One B-rep face of a CAD part: STEP entity #11586.
In plain terms, the planar face has unit normal (0, 1, 0).
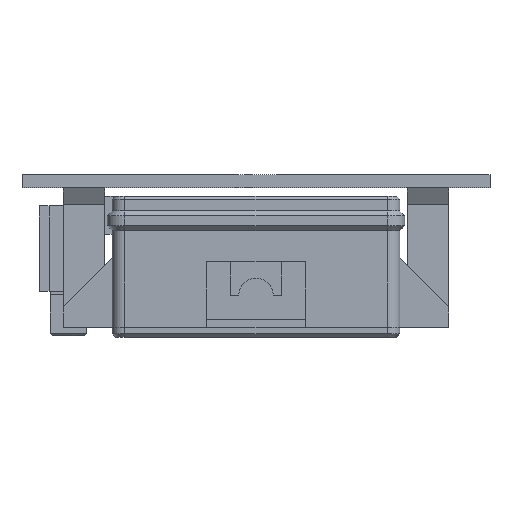
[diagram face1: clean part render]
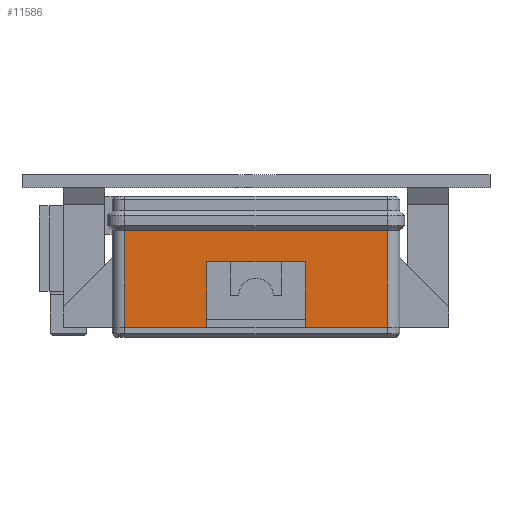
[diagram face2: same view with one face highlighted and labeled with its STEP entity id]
Its self-contained STEP definition (entity closure, numbers rounded to 3 decimals):
#2296 = PLANE('',#2297);
#2297 = AXIS2_PLACEMENT_3D('',#2298,#2299,#2300);
#2298 = CARTESIAN_POINT('',(-35.05,-46.3,32.));
#2299 = DIRECTION('',(0.,0.,1.));
#2300 = DIRECTION('',(1.,0.,-0.));
#5580 = VERTEX_POINT('',#5581);
#5581 = CARTESIAN_POINT('',(32.05,46.3,32.));
#5596 = CYLINDRICAL_SURFACE('',#5597,3.);
#5597 = AXIS2_PLACEMENT_3D('',#5598,#5599,#5600);
#5598 = CARTESIAN_POINT('',(32.05,43.3,0.));
#5599 = DIRECTION('',(0.,0.,1.));
#5600 = DIRECTION('',(1.,0.,-0.));
#5608 = EDGE_CURVE('',#5609,#5580,#5611,.T.);
#5609 = VERTEX_POINT('',#5610);
#5610 = CARTESIAN_POINT('',(12.,46.3,32.));
#5611 = SURFACE_CURVE('',#5612,(#5616,#5623),.PCURVE_S1.);
#5612 = LINE('',#5613,#5614);
#5613 = CARTESIAN_POINT('',(-35.05,46.3,32.));
#5614 = VECTOR('',#5615,1.);
#5615 = DIRECTION('',(1.,0.,-0.));
#5616 = PCURVE('',#2296,#5617);
#5617 = DEFINITIONAL_REPRESENTATION('',(#5618),#5622);
#5618 = LINE('',#5619,#5620);
#5619 = CARTESIAN_POINT('',(0.,92.6));
#5620 = VECTOR('',#5621,1.);
#5621 = DIRECTION('',(1.,0.));
#5622 = ( GEOMETRIC_REPRESENTATION_CONTEXT(2) 
PARAMETRIC_REPRESENTATION_CONTEXT() REPRESENTATION_CONTEXT('2D SPACE',''
  ) );
#5623 = PCURVE('',#5624,#5629);
#5624 = PLANE('',#5625);
#5625 = AXIS2_PLACEMENT_3D('',#5626,#5627,#5628);
#5626 = CARTESIAN_POINT('',(-35.05,46.3,0.));
#5627 = DIRECTION('',(-0.,1.,0.));
#5628 = DIRECTION('',(0.,0.,1.));
#5629 = DEFINITIONAL_REPRESENTATION('',(#5630),#5634);
#5630 = LINE('',#5631,#5632);
#5631 = CARTESIAN_POINT('',(32.,0.));
#5632 = VECTOR('',#5633,1.);
#5633 = DIRECTION('',(0.,1.));
#5634 = ( GEOMETRIC_REPRESENTATION_CONTEXT(2) 
PARAMETRIC_REPRESENTATION_CONTEXT() REPRESENTATION_CONTEXT('2D SPACE',''
  ) );
#5652 = PLANE('',#5653);
#5653 = AXIS2_PLACEMENT_3D('',#5654,#5655,#5656);
#5654 = CARTESIAN_POINT('',(12.,43.5,16.));
#5655 = DIRECTION('',(1.,0.,-0.));
#5656 = DIRECTION('',(0.,0.,1.));
#7690 = CYLINDRICAL_SURFACE('',#7691,3.);
#7691 = AXIS2_PLACEMENT_3D('',#7692,#7693,#7694);
#7692 = CARTESIAN_POINT('',(-32.05,43.3,0.));
#7693 = DIRECTION('',(0.,0.,1.));
#7694 = DIRECTION('',(-1.,-0.,0.));
#7718 = PLANE('',#7719);
#7719 = AXIS2_PLACEMENT_3D('',#7720,#7721,#7722);
#7720 = CARTESIAN_POINT('',(-35.05,-46.3,32.));
#7721 = DIRECTION('',(0.,0.,1.));
#7722 = DIRECTION('',(1.,0.,-0.));
#11537 = VERTEX_POINT('',#11538);
#11538 = CARTESIAN_POINT('',(32.05,46.3,8.4));
#11565 = EDGE_CURVE('',#11537,#5580,#11566,.T.);
#11566 = SURFACE_CURVE('',#11567,(#11571,#11578),.PCURVE_S1.);
#11567 = LINE('',#11568,#11569);
#11568 = CARTESIAN_POINT('',(32.05,46.3,0.));
#11569 = VECTOR('',#11570,1.);
#11570 = DIRECTION('',(0.,0.,1.));
#11571 = PCURVE('',#5596,#11572);
#11572 = DEFINITIONAL_REPRESENTATION('',(#11573),#11577);
#11573 = LINE('',#11574,#11575);
#11574 = CARTESIAN_POINT('',(1.571,0.));
#11575 = VECTOR('',#11576,1.);
#11576 = DIRECTION('',(0.,1.));
#11577 = ( GEOMETRIC_REPRESENTATION_CONTEXT(2) 
PARAMETRIC_REPRESENTATION_CONTEXT() REPRESENTATION_CONTEXT('2D SPACE',''
  ) );
#11578 = PCURVE('',#5624,#11579);
#11579 = DEFINITIONAL_REPRESENTATION('',(#11580),#11584);
#11580 = LINE('',#11581,#11582);
#11581 = CARTESIAN_POINT('',(0.,67.1));
#11582 = VECTOR('',#11583,1.);
#11583 = DIRECTION('',(1.,0.));
#11584 = ( GEOMETRIC_REPRESENTATION_CONTEXT(2) 
PARAMETRIC_REPRESENTATION_CONTEXT() REPRESENTATION_CONTEXT('2D SPACE',''
  ) );
#11586 = ADVANCED_FACE('',(#11587),#5624,.T.);
#11587 = FACE_BOUND('',#11588,.T.);
#11588 = EDGE_LOOP('',(#11589,#11617,#11640,#11663,#11689,#11715,#11734,
    #11735));
#11589 = ORIENTED_EDGE('',*,*,#11590,.F.);
#11590 = EDGE_CURVE('',#11591,#11537,#11593,.T.);
#11591 = VERTEX_POINT('',#11592);
#11592 = CARTESIAN_POINT('',(-32.05,46.3,8.4));
#11593 = SURFACE_CURVE('',#11594,(#11598,#11605),.PCURVE_S1.);
#11594 = LINE('',#11595,#11596);
#11595 = CARTESIAN_POINT('',(-32.05,46.3,8.4));
#11596 = VECTOR('',#11597,1.);
#11597 = DIRECTION('',(1.,0.,-0.));
#11598 = PCURVE('',#5624,#11599);
#11599 = DEFINITIONAL_REPRESENTATION('',(#11600),#11604);
#11600 = LINE('',#11601,#11602);
#11601 = CARTESIAN_POINT('',(8.4,3.));
#11602 = VECTOR('',#11603,1.);
#11603 = DIRECTION('',(0.,1.));
#11604 = ( GEOMETRIC_REPRESENTATION_CONTEXT(2) 
PARAMETRIC_REPRESENTATION_CONTEXT() REPRESENTATION_CONTEXT('2D SPACE',''
  ) );
#11605 = PCURVE('',#11606,#11611);
#11606 = PLANE('',#11607);
#11607 = AXIS2_PLACEMENT_3D('',#11608,#11609,#11610);
#11608 = CARTESIAN_POINT('',(-32.05,46.9,7.8));
#11609 = DIRECTION('',(0.,0.707,0.707));
#11610 = DIRECTION('',(-1.,-0.,0.));
#11611 = DEFINITIONAL_REPRESENTATION('',(#11612),#11616);
#11612 = LINE('',#11613,#11614);
#11613 = CARTESIAN_POINT('',(-0.,0.849));
#11614 = VECTOR('',#11615,1.);
#11615 = DIRECTION('',(-1.,0.));
#11616 = ( GEOMETRIC_REPRESENTATION_CONTEXT(2) 
PARAMETRIC_REPRESENTATION_CONTEXT() REPRESENTATION_CONTEXT('2D SPACE',''
  ) );
#11617 = ORIENTED_EDGE('',*,*,#11618,.T.);
#11618 = EDGE_CURVE('',#11591,#11619,#11621,.T.);
#11619 = VERTEX_POINT('',#11620);
#11620 = CARTESIAN_POINT('',(-32.05,46.3,32.));
#11621 = SURFACE_CURVE('',#11622,(#11626,#11633),.PCURVE_S1.);
#11622 = LINE('',#11623,#11624);
#11623 = CARTESIAN_POINT('',(-32.05,46.3,0.));
#11624 = VECTOR('',#11625,1.);
#11625 = DIRECTION('',(0.,0.,1.));
#11626 = PCURVE('',#5624,#11627);
#11627 = DEFINITIONAL_REPRESENTATION('',(#11628),#11632);
#11628 = LINE('',#11629,#11630);
#11629 = CARTESIAN_POINT('',(0.,3.));
#11630 = VECTOR('',#11631,1.);
#11631 = DIRECTION('',(1.,0.));
#11632 = ( GEOMETRIC_REPRESENTATION_CONTEXT(2) 
PARAMETRIC_REPRESENTATION_CONTEXT() REPRESENTATION_CONTEXT('2D SPACE',''
  ) );
#11633 = PCURVE('',#7690,#11634);
#11634 = DEFINITIONAL_REPRESENTATION('',(#11635),#11639);
#11635 = LINE('',#11636,#11637);
#11636 = CARTESIAN_POINT('',(-1.571,0.));
#11637 = VECTOR('',#11638,1.);
#11638 = DIRECTION('',(-0.,1.));
#11639 = ( GEOMETRIC_REPRESENTATION_CONTEXT(2) 
PARAMETRIC_REPRESENTATION_CONTEXT() REPRESENTATION_CONTEXT('2D SPACE',''
  ) );
#11640 = ORIENTED_EDGE('',*,*,#11641,.T.);
#11641 = EDGE_CURVE('',#11619,#11642,#11644,.T.);
#11642 = VERTEX_POINT('',#11643);
#11643 = CARTESIAN_POINT('',(-12.,46.3,32.));
#11644 = SURFACE_CURVE('',#11645,(#11649,#11656),.PCURVE_S1.);
#11645 = LINE('',#11646,#11647);
#11646 = CARTESIAN_POINT('',(-35.05,46.3,32.));
#11647 = VECTOR('',#11648,1.);
#11648 = DIRECTION('',(1.,0.,-0.));
#11649 = PCURVE('',#5624,#11650);
#11650 = DEFINITIONAL_REPRESENTATION('',(#11651),#11655);
#11651 = LINE('',#11652,#11653);
#11652 = CARTESIAN_POINT('',(32.,0.));
#11653 = VECTOR('',#11654,1.);
#11654 = DIRECTION('',(0.,1.));
#11655 = ( GEOMETRIC_REPRESENTATION_CONTEXT(2) 
PARAMETRIC_REPRESENTATION_CONTEXT() REPRESENTATION_CONTEXT('2D SPACE',''
  ) );
#11656 = PCURVE('',#7718,#11657);
#11657 = DEFINITIONAL_REPRESENTATION('',(#11658),#11662);
#11658 = LINE('',#11659,#11660);
#11659 = CARTESIAN_POINT('',(0.,92.6));
#11660 = VECTOR('',#11661,1.);
#11661 = DIRECTION('',(1.,0.));
#11662 = ( GEOMETRIC_REPRESENTATION_CONTEXT(2) 
PARAMETRIC_REPRESENTATION_CONTEXT() REPRESENTATION_CONTEXT('2D SPACE',''
  ) );
#11663 = ORIENTED_EDGE('',*,*,#11664,.T.);
#11664 = EDGE_CURVE('',#11642,#11665,#11667,.T.);
#11665 = VERTEX_POINT('',#11666);
#11666 = CARTESIAN_POINT('',(-12.,46.3,16.));
#11667 = SURFACE_CURVE('',#11668,(#11672,#11678),.PCURVE_S1.);
#11668 = LINE('',#11669,#11670);
#11669 = CARTESIAN_POINT('',(-12.,46.3,8.));
#11670 = VECTOR('',#11671,1.);
#11671 = DIRECTION('',(-0.,0.,-1.));
#11672 = PCURVE('',#5624,#11673);
#11673 = DEFINITIONAL_REPRESENTATION('',(#11674),#11677);
#11674 = B_SPLINE_CURVE_WITH_KNOTS('',1,(#11675,#11676),.UNSPECIFIED.,
  .F.,.F.,(2,2),(-24.,-8.),.PIECEWISE_BEZIER_KNOTS.);
#11675 = CARTESIAN_POINT('',(32.,23.05));
#11676 = CARTESIAN_POINT('',(16.,23.05));
#11677 = ( GEOMETRIC_REPRESENTATION_CONTEXT(2) 
PARAMETRIC_REPRESENTATION_CONTEXT() REPRESENTATION_CONTEXT('2D SPACE',''
  ) );
#11678 = PCURVE('',#11679,#11684);
#11679 = PLANE('',#11680);
#11680 = AXIS2_PLACEMENT_3D('',#11681,#11682,#11683);
#11681 = CARTESIAN_POINT('',(-12.,43.5,16.));
#11682 = DIRECTION('',(1.,0.,-0.));
#11683 = DIRECTION('',(0.,0.,1.));
#11684 = DEFINITIONAL_REPRESENTATION('',(#11685),#11688);
#11685 = B_SPLINE_CURVE_WITH_KNOTS('',1,(#11686,#11687),.UNSPECIFIED.,
  .F.,.F.,(2,2),(-24.,-8.),.PIECEWISE_BEZIER_KNOTS.);
#11686 = CARTESIAN_POINT('',(16.,-2.8));
#11687 = CARTESIAN_POINT('',(0.,-2.8));
#11688 = ( GEOMETRIC_REPRESENTATION_CONTEXT(2) 
PARAMETRIC_REPRESENTATION_CONTEXT() REPRESENTATION_CONTEXT('2D SPACE',''
  ) );
#11689 = ORIENTED_EDGE('',*,*,#11690,.T.);
#11690 = EDGE_CURVE('',#11665,#11691,#11693,.T.);
#11691 = VERTEX_POINT('',#11692);
#11692 = CARTESIAN_POINT('',(12.,46.3,16.));
#11693 = SURFACE_CURVE('',#11694,(#11698,#11704),.PCURVE_S1.);
#11694 = LINE('',#11695,#11696);
#11695 = CARTESIAN_POINT('',(-23.525,46.3,16.));
#11696 = VECTOR('',#11697,1.);
#11697 = DIRECTION('',(1.,0.,-0.));
#11698 = PCURVE('',#5624,#11699);
#11699 = DEFINITIONAL_REPRESENTATION('',(#11700),#11703);
#11700 = B_SPLINE_CURVE_WITH_KNOTS('',1,(#11701,#11702),.UNSPECIFIED.,
  .F.,.F.,(2,2),(11.525,35.525),.PIECEWISE_BEZIER_KNOTS.);
#11701 = CARTESIAN_POINT('',(16.,23.05));
#11702 = CARTESIAN_POINT('',(16.,47.05));
#11703 = ( GEOMETRIC_REPRESENTATION_CONTEXT(2) 
PARAMETRIC_REPRESENTATION_CONTEXT() REPRESENTATION_CONTEXT('2D SPACE',''
  ) );
#11704 = PCURVE('',#11705,#11710);
#11705 = PLANE('',#11706);
#11706 = AXIS2_PLACEMENT_3D('',#11707,#11708,#11709);
#11707 = CARTESIAN_POINT('',(-12.,43.5,16.));
#11708 = DIRECTION('',(0.,0.,1.));
#11709 = DIRECTION('',(1.,0.,-0.));
#11710 = DEFINITIONAL_REPRESENTATION('',(#11711),#11714);
#11711 = B_SPLINE_CURVE_WITH_KNOTS('',1,(#11712,#11713),.UNSPECIFIED.,
  .F.,.F.,(2,2),(11.525,35.525),.PIECEWISE_BEZIER_KNOTS.);
#11712 = CARTESIAN_POINT('',(0.,2.8));
#11713 = CARTESIAN_POINT('',(24.,2.8));
#11714 = ( GEOMETRIC_REPRESENTATION_CONTEXT(2) 
PARAMETRIC_REPRESENTATION_CONTEXT() REPRESENTATION_CONTEXT('2D SPACE',''
  ) );
#11715 = ORIENTED_EDGE('',*,*,#11716,.F.);
#11716 = EDGE_CURVE('',#5609,#11691,#11717,.T.);
#11717 = SURFACE_CURVE('',#11718,(#11722,#11728),.PCURVE_S1.);
#11718 = LINE('',#11719,#11720);
#11719 = CARTESIAN_POINT('',(12.,46.3,8.));
#11720 = VECTOR('',#11721,1.);
#11721 = DIRECTION('',(-0.,0.,-1.));
#11722 = PCURVE('',#5624,#11723);
#11723 = DEFINITIONAL_REPRESENTATION('',(#11724),#11727);
#11724 = B_SPLINE_CURVE_WITH_KNOTS('',1,(#11725,#11726),.UNSPECIFIED.,
  .F.,.F.,(2,2),(-24.,-8.),.PIECEWISE_BEZIER_KNOTS.);
#11725 = CARTESIAN_POINT('',(32.,47.05));
#11726 = CARTESIAN_POINT('',(16.,47.05));
#11727 = ( GEOMETRIC_REPRESENTATION_CONTEXT(2) 
PARAMETRIC_REPRESENTATION_CONTEXT() REPRESENTATION_CONTEXT('2D SPACE',''
  ) );
#11728 = PCURVE('',#5652,#11729);
#11729 = DEFINITIONAL_REPRESENTATION('',(#11730),#11733);
#11730 = B_SPLINE_CURVE_WITH_KNOTS('',1,(#11731,#11732),.UNSPECIFIED.,
  .F.,.F.,(2,2),(-24.,-8.),.PIECEWISE_BEZIER_KNOTS.);
#11731 = CARTESIAN_POINT('',(16.,-2.8));
#11732 = CARTESIAN_POINT('',(0.,-2.8));
#11733 = ( GEOMETRIC_REPRESENTATION_CONTEXT(2) 
PARAMETRIC_REPRESENTATION_CONTEXT() REPRESENTATION_CONTEXT('2D SPACE',''
  ) );
#11734 = ORIENTED_EDGE('',*,*,#5608,.T.);
#11735 = ORIENTED_EDGE('',*,*,#11565,.F.);
